One B-rep face of a CAD part: STEP entity #45918.
In plain terms, the planar face has unit normal (0, 0, 1).
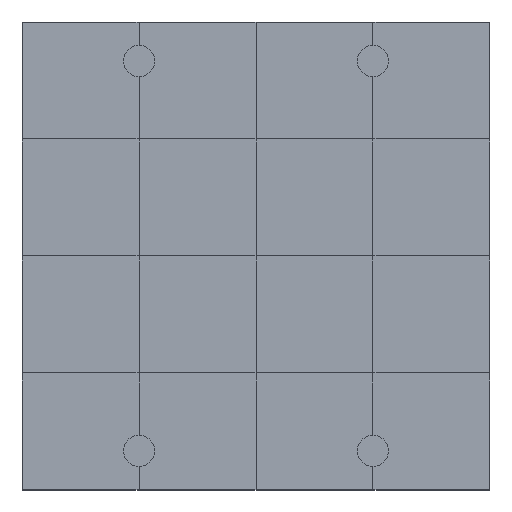
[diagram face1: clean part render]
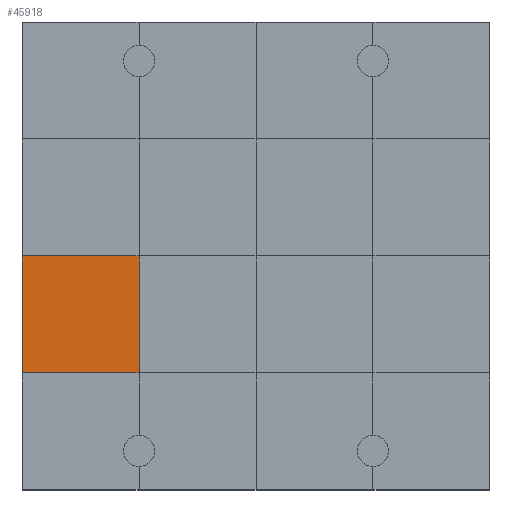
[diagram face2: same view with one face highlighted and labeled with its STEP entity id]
Its self-contained STEP definition (entity closure, numbers rounded to 3 decimals):
#45468 = VERTEX_POINT('',#45469);
#45469 = CARTESIAN_POINT('',(0.,3.,1.2));
#45483 = PLANE('',#45484);
#45484 = AXIS2_PLACEMENT_3D('',#45485,#45486,#45487);
#45485 = CARTESIAN_POINT('',(0.,3.,0.));
#45486 = DIRECTION('',(1.,0.,-0.));
#45487 = DIRECTION('',(0.,0.,1.));
#45509 = PLANE('',#45510);
#45510 = AXIS2_PLACEMENT_3D('',#45511,#45512,#45513);
#45511 = CARTESIAN_POINT('',(0.,0.,1.2));
#45512 = DIRECTION('',(0.,0.,1.));
#45513 = DIRECTION('',(1.,0.,-0.));
#45660 = VERTEX_POINT('',#45661);
#45661 = CARTESIAN_POINT('',(3.,3.,1.2));
#45682 = EDGE_CURVE('',#45468,#45660,#45683,.T.);
#45683 = SURFACE_CURVE('',#45684,(#45688,#45695),.PCURVE_S1.);
#45684 = LINE('',#45685,#45686);
#45685 = CARTESIAN_POINT('',(0.,3.,1.2));
#45686 = VECTOR('',#45687,1.);
#45687 = DIRECTION('',(1.,0.,-0.));
#45688 = PCURVE('',#45509,#45689);
#45689 = DEFINITIONAL_REPRESENTATION('',(#45690),#45694);
#45690 = LINE('',#45691,#45692);
#45691 = CARTESIAN_POINT('',(0.,3.));
#45692 = VECTOR('',#45693,1.);
#45693 = DIRECTION('',(1.,0.));
#45694 = ( GEOMETRIC_REPRESENTATION_CONTEXT(2) 
PARAMETRIC_REPRESENTATION_CONTEXT() REPRESENTATION_CONTEXT('2D SPACE',''
  ) );
#45695 = PCURVE('',#45696,#45701);
#45696 = PLANE('',#45697);
#45697 = AXIS2_PLACEMENT_3D('',#45698,#45699,#45700);
#45698 = CARTESIAN_POINT('',(0.,3.,1.2));
#45699 = DIRECTION('',(0.,0.,1.));
#45700 = DIRECTION('',(1.,0.,-0.));
#45701 = DEFINITIONAL_REPRESENTATION('',(#45702),#45706);
#45702 = LINE('',#45703,#45704);
#45703 = CARTESIAN_POINT('',(0.,0.));
#45704 = VECTOR('',#45705,1.);
#45705 = DIRECTION('',(1.,0.));
#45706 = ( GEOMETRIC_REPRESENTATION_CONTEXT(2) 
PARAMETRIC_REPRESENTATION_CONTEXT() REPRESENTATION_CONTEXT('2D SPACE',''
  ) );
#45741 = VERTEX_POINT('',#45742);
#45742 = CARTESIAN_POINT('',(0.,6.,1.2));
#45768 = EDGE_CURVE('',#45468,#45741,#45769,.T.);
#45769 = SURFACE_CURVE('',#45770,(#45774,#45781),.PCURVE_S1.);
#45770 = LINE('',#45771,#45772);
#45771 = CARTESIAN_POINT('',(0.,3.,1.2));
#45772 = VECTOR('',#45773,1.);
#45773 = DIRECTION('',(-0.,1.,0.));
#45774 = PCURVE('',#45483,#45775);
#45775 = DEFINITIONAL_REPRESENTATION('',(#45776),#45780);
#45776 = LINE('',#45777,#45778);
#45777 = CARTESIAN_POINT('',(1.2,0.));
#45778 = VECTOR('',#45779,1.);
#45779 = DIRECTION('',(0.,-1.));
#45780 = ( GEOMETRIC_REPRESENTATION_CONTEXT(2) 
PARAMETRIC_REPRESENTATION_CONTEXT() REPRESENTATION_CONTEXT('2D SPACE',''
  ) );
#45781 = PCURVE('',#45696,#45782);
#45782 = DEFINITIONAL_REPRESENTATION('',(#45783),#45787);
#45783 = LINE('',#45784,#45785);
#45784 = CARTESIAN_POINT('',(0.,0.));
#45785 = VECTOR('',#45786,1.);
#45786 = DIRECTION('',(0.,1.));
#45787 = ( GEOMETRIC_REPRESENTATION_CONTEXT(2) 
PARAMETRIC_REPRESENTATION_CONTEXT() REPRESENTATION_CONTEXT('2D SPACE',''
  ) );
#45918 = ADVANCED_FACE('',(#45919),#45696,.T.);
#45919 = FACE_BOUND('',#45920,.T.);
#45920 = EDGE_LOOP('',(#45921,#45922,#45923,#45951));
#45921 = ORIENTED_EDGE('',*,*,#45768,.F.);
#45922 = ORIENTED_EDGE('',*,*,#45682,.T.);
#45923 = ORIENTED_EDGE('',*,*,#45924,.T.);
#45924 = EDGE_CURVE('',#45660,#45925,#45927,.T.);
#45925 = VERTEX_POINT('',#45926);
#45926 = CARTESIAN_POINT('',(3.,6.,1.2));
#45927 = SURFACE_CURVE('',#45928,(#45932,#45939),.PCURVE_S1.);
#45928 = LINE('',#45929,#45930);
#45929 = CARTESIAN_POINT('',(3.,3.,1.2));
#45930 = VECTOR('',#45931,1.);
#45931 = DIRECTION('',(-0.,1.,0.));
#45932 = PCURVE('',#45696,#45933);
#45933 = DEFINITIONAL_REPRESENTATION('',(#45934),#45938);
#45934 = LINE('',#45935,#45936);
#45935 = CARTESIAN_POINT('',(3.,0.));
#45936 = VECTOR('',#45937,1.);
#45937 = DIRECTION('',(0.,1.));
#45938 = ( GEOMETRIC_REPRESENTATION_CONTEXT(2) 
PARAMETRIC_REPRESENTATION_CONTEXT() REPRESENTATION_CONTEXT('2D SPACE',''
  ) );
#45939 = PCURVE('',#45940,#45945);
#45940 = PLANE('',#45941);
#45941 = AXIS2_PLACEMENT_3D('',#45942,#45943,#45944);
#45942 = CARTESIAN_POINT('',(3.,3.,1.2));
#45943 = DIRECTION('',(0.,0.,1.));
#45944 = DIRECTION('',(1.,0.,-0.));
#45945 = DEFINITIONAL_REPRESENTATION('',(#45946),#45950);
#45946 = LINE('',#45947,#45948);
#45947 = CARTESIAN_POINT('',(0.,0.));
#45948 = VECTOR('',#45949,1.);
#45949 = DIRECTION('',(0.,1.));
#45950 = ( GEOMETRIC_REPRESENTATION_CONTEXT(2) 
PARAMETRIC_REPRESENTATION_CONTEXT() REPRESENTATION_CONTEXT('2D SPACE',''
  ) );
#45951 = ORIENTED_EDGE('',*,*,#45952,.F.);
#45952 = EDGE_CURVE('',#45741,#45925,#45953,.T.);
#45953 = SURFACE_CURVE('',#45954,(#45958,#45965),.PCURVE_S1.);
#45954 = LINE('',#45955,#45956);
#45955 = CARTESIAN_POINT('',(0.,6.,1.2));
#45956 = VECTOR('',#45957,1.);
#45957 = DIRECTION('',(1.,0.,-0.));
#45958 = PCURVE('',#45696,#45959);
#45959 = DEFINITIONAL_REPRESENTATION('',(#45960),#45964);
#45960 = LINE('',#45961,#45962);
#45961 = CARTESIAN_POINT('',(0.,3.));
#45962 = VECTOR('',#45963,1.);
#45963 = DIRECTION('',(1.,0.));
#45964 = ( GEOMETRIC_REPRESENTATION_CONTEXT(2) 
PARAMETRIC_REPRESENTATION_CONTEXT() REPRESENTATION_CONTEXT('2D SPACE',''
  ) );
#45965 = PCURVE('',#45966,#45971);
#45966 = PLANE('',#45967);
#45967 = AXIS2_PLACEMENT_3D('',#45968,#45969,#45970);
#45968 = CARTESIAN_POINT('',(0.,6.,1.2));
#45969 = DIRECTION('',(0.,0.,1.));
#45970 = DIRECTION('',(1.,0.,-0.));
#45971 = DEFINITIONAL_REPRESENTATION('',(#45972),#45976);
#45972 = LINE('',#45973,#45974);
#45973 = CARTESIAN_POINT('',(0.,0.));
#45974 = VECTOR('',#45975,1.);
#45975 = DIRECTION('',(1.,0.));
#45976 = ( GEOMETRIC_REPRESENTATION_CONTEXT(2) 
PARAMETRIC_REPRESENTATION_CONTEXT() REPRESENTATION_CONTEXT('2D SPACE',''
  ) );
